VERSION 5.8 ;
BUSBITCHARS "[]" ;
DIVIDERCHAR "/" ;
UNITS
    DATABASE MICRONS 2000 ;
END UNITS

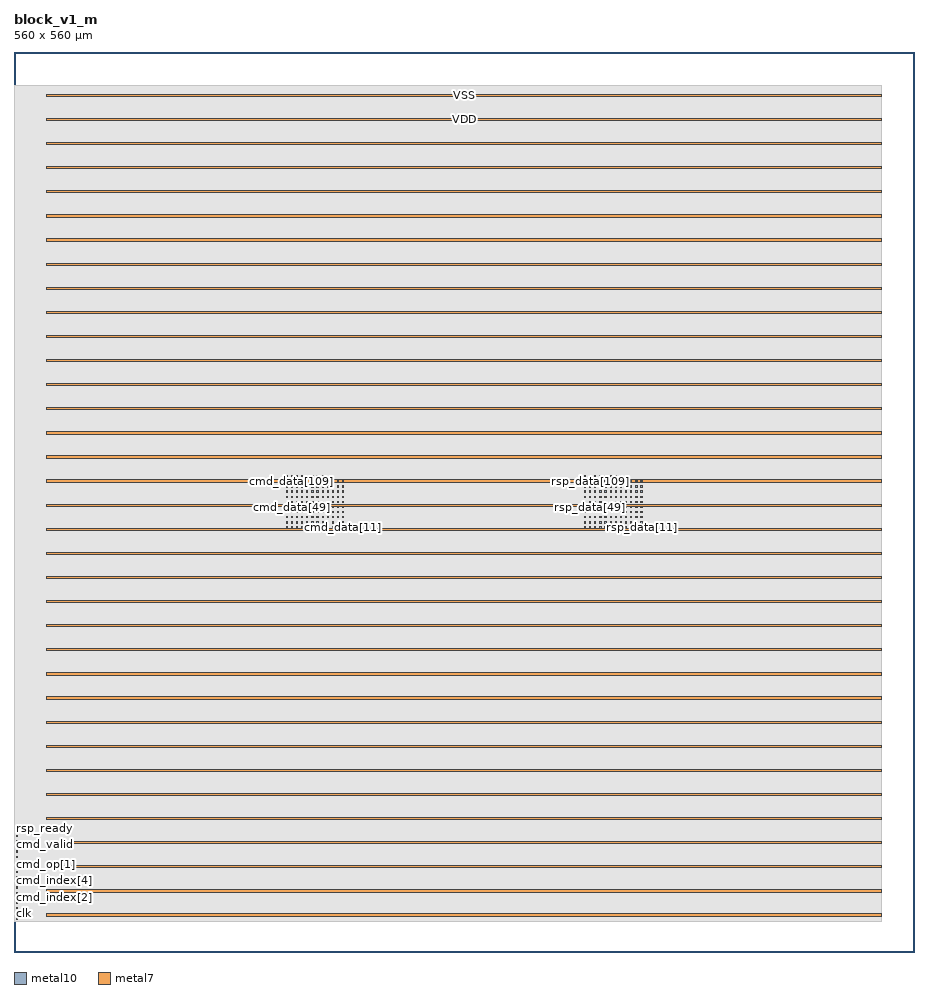
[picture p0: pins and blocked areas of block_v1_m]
MACRO block_v1_m
  FOREIGN block_v1_m 0 0 ;
  CLASS BLOCK ;
  SIZE 560 BY 560 ;
  PIN busy
    DIRECTION OUTPUT ;
    USE SIGNAL ;
    PORT
      LAYER metal10 ;
        RECT  1.295 20.47 2.095 21.27 ;
    END
  END busy
  PIN clk
    DIRECTION INPUT ;
    USE SIGNAL ;
    PORT
      LAYER metal10 ;
        RECT  1.295 23.67 2.095 24.47 ;
    END
  END clk
  PIN cmd_data[0]
    DIRECTION INPUT ;
    USE SIGNAL ;
    PORT
      LAYER metal10 ;
        RECT  169.295 263.67 170.095 264.47 ;
    END
  END cmd_data[0]
  PIN cmd_data[100]
    DIRECTION INPUT ;
    USE SIGNAL ;
    PORT
      LAYER metal10 ;
        RECT  182.095 289.27 182.895 290.07 ;
    END
  END cmd_data[100]
  PIN cmd_data[101]
    DIRECTION INPUT ;
    USE SIGNAL ;
    PORT
      LAYER metal10 ;
        RECT  185.295 289.27 186.095 290.07 ;
    END
  END cmd_data[101]
  PIN cmd_data[102]
    DIRECTION INPUT ;
    USE SIGNAL ;
    PORT
      LAYER metal10 ;
        RECT  188.495 289.27 189.295 290.07 ;
    END
  END cmd_data[102]
  PIN cmd_data[103]
    DIRECTION INPUT ;
    USE SIGNAL ;
    PORT
      LAYER metal10 ;
        RECT  191.695 289.27 192.495 290.07 ;
    END
  END cmd_data[103]
  PIN cmd_data[104]
    DIRECTION INPUT ;
    USE SIGNAL ;
    PORT
      LAYER metal10 ;
        RECT  194.895 289.27 195.695 290.07 ;
    END
  END cmd_data[104]
  PIN cmd_data[105]
    DIRECTION INPUT ;
    USE SIGNAL ;
    PORT
      LAYER metal10 ;
        RECT  198.095 289.27 198.895 290.07 ;
    END
  END cmd_data[105]
  PIN cmd_data[106]
    DIRECTION INPUT ;
    USE SIGNAL ;
    PORT
      LAYER metal10 ;
        RECT  201.295 289.27 202.095 290.07 ;
    END
  END cmd_data[106]
  PIN cmd_data[107]
    DIRECTION INPUT ;
    USE SIGNAL ;
    PORT
      LAYER metal10 ;
        RECT  204.495 289.27 205.295 290.07 ;
    END
  END cmd_data[107]
  PIN cmd_data[108]
    DIRECTION INPUT ;
    USE SIGNAL ;
    PORT
      LAYER metal10 ;
        RECT  169.295 292.47 170.095 293.27 ;
    END
  END cmd_data[108]
  PIN cmd_data[109]
    DIRECTION INPUT ;
    USE SIGNAL ;
    PORT
      LAYER metal10 ;
        RECT  172.495 292.47 173.295 293.27 ;
    END
  END cmd_data[109]
  PIN cmd_data[10]
    DIRECTION INPUT ;
    USE SIGNAL ;
    PORT
      LAYER metal10 ;
        RECT  201.295 263.67 202.095 264.47 ;
    END
  END cmd_data[10]
  PIN cmd_data[110]
    DIRECTION INPUT ;
    USE SIGNAL ;
    PORT
      LAYER metal10 ;
        RECT  175.695 292.47 176.495 293.27 ;
    END
  END cmd_data[110]
  PIN cmd_data[111]
    DIRECTION INPUT ;
    USE SIGNAL ;
    PORT
      LAYER metal10 ;
        RECT  178.895 292.47 179.695 293.27 ;
    END
  END cmd_data[111]
  PIN cmd_data[112]
    DIRECTION INPUT ;
    USE SIGNAL ;
    PORT
      LAYER metal10 ;
        RECT  182.095 292.47 182.895 293.27 ;
    END
  END cmd_data[112]
  PIN cmd_data[113]
    DIRECTION INPUT ;
    USE SIGNAL ;
    PORT
      LAYER metal10 ;
        RECT  185.295 292.47 186.095 293.27 ;
    END
  END cmd_data[113]
  PIN cmd_data[114]
    DIRECTION INPUT ;
    USE SIGNAL ;
    PORT
      LAYER metal10 ;
        RECT  188.495 292.47 189.295 293.27 ;
    END
  END cmd_data[114]
  PIN cmd_data[115]
    DIRECTION INPUT ;
    USE SIGNAL ;
    PORT
      LAYER metal10 ;
        RECT  191.695 292.47 192.495 293.27 ;
    END
  END cmd_data[115]
  PIN cmd_data[116]
    DIRECTION INPUT ;
    USE SIGNAL ;
    PORT
      LAYER metal10 ;
        RECT  194.895 292.47 195.695 293.27 ;
    END
  END cmd_data[116]
  PIN cmd_data[117]
    DIRECTION INPUT ;
    USE SIGNAL ;
    PORT
      LAYER metal10 ;
        RECT  198.095 292.47 198.895 293.27 ;
    END
  END cmd_data[117]
  PIN cmd_data[118]
    DIRECTION INPUT ;
    USE SIGNAL ;
    PORT
      LAYER metal10 ;
        RECT  201.295 292.47 202.095 293.27 ;
    END
  END cmd_data[118]
  PIN cmd_data[119]
    DIRECTION INPUT ;
    USE SIGNAL ;
    PORT
      LAYER metal10 ;
        RECT  204.495 292.47 205.295 293.27 ;
    END
  END cmd_data[119]
  PIN cmd_data[11]
    DIRECTION INPUT ;
    USE SIGNAL ;
    PORT
      LAYER metal10 ;
        RECT  204.495 263.67 205.295 264.47 ;
    END
  END cmd_data[11]
  PIN cmd_data[120]
    DIRECTION INPUT ;
    USE SIGNAL ;
    PORT
      LAYER metal10 ;
        RECT  169.295 295.67 170.095 296.47 ;
    END
  END cmd_data[120]
  PIN cmd_data[121]
    DIRECTION INPUT ;
    USE SIGNAL ;
    PORT
      LAYER metal10 ;
        RECT  172.495 295.67 173.295 296.47 ;
    END
  END cmd_data[121]
  PIN cmd_data[122]
    DIRECTION INPUT ;
    USE SIGNAL ;
    PORT
      LAYER metal10 ;
        RECT  175.695 295.67 176.495 296.47 ;
    END
  END cmd_data[122]
  PIN cmd_data[123]
    DIRECTION INPUT ;
    USE SIGNAL ;
    PORT
      LAYER metal10 ;
        RECT  178.895 295.67 179.695 296.47 ;
    END
  END cmd_data[123]
  PIN cmd_data[124]
    DIRECTION INPUT ;
    USE SIGNAL ;
    PORT
      LAYER metal10 ;
        RECT  182.095 295.67 182.895 296.47 ;
    END
  END cmd_data[124]
  PIN cmd_data[125]
    DIRECTION INPUT ;
    USE SIGNAL ;
    PORT
      LAYER metal10 ;
        RECT  185.295 295.67 186.095 296.47 ;
    END
  END cmd_data[125]
  PIN cmd_data[126]
    DIRECTION INPUT ;
    USE SIGNAL ;
    PORT
      LAYER metal10 ;
        RECT  188.495 295.67 189.295 296.47 ;
    END
  END cmd_data[126]
  PIN cmd_data[127]
    DIRECTION INPUT ;
    USE SIGNAL ;
    PORT
      LAYER metal10 ;
        RECT  191.695 295.67 192.495 296.47 ;
    END
  END cmd_data[127]
  PIN cmd_data[12]
    DIRECTION INPUT ;
    USE SIGNAL ;
    PORT
      LAYER metal10 ;
        RECT  169.295 266.87 170.095 267.67 ;
    END
  END cmd_data[12]
  PIN cmd_data[13]
    DIRECTION INPUT ;
    USE SIGNAL ;
    PORT
      LAYER metal10 ;
        RECT  172.495 266.87 173.295 267.67 ;
    END
  END cmd_data[13]
  PIN cmd_data[14]
    DIRECTION INPUT ;
    USE SIGNAL ;
    PORT
      LAYER metal10 ;
        RECT  175.695 266.87 176.495 267.67 ;
    END
  END cmd_data[14]
  PIN cmd_data[15]
    DIRECTION INPUT ;
    USE SIGNAL ;
    PORT
      LAYER metal10 ;
        RECT  178.895 266.87 179.695 267.67 ;
    END
  END cmd_data[15]
  PIN cmd_data[16]
    DIRECTION INPUT ;
    USE SIGNAL ;
    PORT
      LAYER metal10 ;
        RECT  182.095 266.87 182.895 267.67 ;
    END
  END cmd_data[16]
  PIN cmd_data[17]
    DIRECTION INPUT ;
    USE SIGNAL ;
    PORT
      LAYER metal10 ;
        RECT  185.295 266.87 186.095 267.67 ;
    END
  END cmd_data[17]
  PIN cmd_data[18]
    DIRECTION INPUT ;
    USE SIGNAL ;
    PORT
      LAYER metal10 ;
        RECT  188.495 266.87 189.295 267.67 ;
    END
  END cmd_data[18]
  PIN cmd_data[19]
    DIRECTION INPUT ;
    USE SIGNAL ;
    PORT
      LAYER metal10 ;
        RECT  191.695 266.87 192.495 267.67 ;
    END
  END cmd_data[19]
  PIN cmd_data[1]
    DIRECTION INPUT ;
    USE SIGNAL ;
    PORT
      LAYER metal10 ;
        RECT  172.495 263.67 173.295 264.47 ;
    END
  END cmd_data[1]
  PIN cmd_data[20]
    DIRECTION INPUT ;
    USE SIGNAL ;
    PORT
      LAYER metal10 ;
        RECT  194.895 266.87 195.695 267.67 ;
    END
  END cmd_data[20]
  PIN cmd_data[21]
    DIRECTION INPUT ;
    USE SIGNAL ;
    PORT
      LAYER metal10 ;
        RECT  198.095 266.87 198.895 267.67 ;
    END
  END cmd_data[21]
  PIN cmd_data[22]
    DIRECTION INPUT ;
    USE SIGNAL ;
    PORT
      LAYER metal10 ;
        RECT  201.295 266.87 202.095 267.67 ;
    END
  END cmd_data[22]
  PIN cmd_data[23]
    DIRECTION INPUT ;
    USE SIGNAL ;
    PORT
      LAYER metal10 ;
        RECT  204.495 266.87 205.295 267.67 ;
    END
  END cmd_data[23]
  PIN cmd_data[24]
    DIRECTION INPUT ;
    USE SIGNAL ;
    PORT
      LAYER metal10 ;
        RECT  169.295 270.07 170.095 270.87 ;
    END
  END cmd_data[24]
  PIN cmd_data[25]
    DIRECTION INPUT ;
    USE SIGNAL ;
    PORT
      LAYER metal10 ;
        RECT  172.495 270.07 173.295 270.87 ;
    END
  END cmd_data[25]
  PIN cmd_data[26]
    DIRECTION INPUT ;
    USE SIGNAL ;
    PORT
      LAYER metal10 ;
        RECT  175.695 270.07 176.495 270.87 ;
    END
  END cmd_data[26]
  PIN cmd_data[27]
    DIRECTION INPUT ;
    USE SIGNAL ;
    PORT
      LAYER metal10 ;
        RECT  178.895 270.07 179.695 270.87 ;
    END
  END cmd_data[27]
  PIN cmd_data[28]
    DIRECTION INPUT ;
    USE SIGNAL ;
    PORT
      LAYER metal10 ;
        RECT  182.095 270.07 182.895 270.87 ;
    END
  END cmd_data[28]
  PIN cmd_data[29]
    DIRECTION INPUT ;
    USE SIGNAL ;
    PORT
      LAYER metal10 ;
        RECT  185.295 270.07 186.095 270.87 ;
    END
  END cmd_data[29]
  PIN cmd_data[2]
    DIRECTION INPUT ;
    USE SIGNAL ;
    PORT
      LAYER metal10 ;
        RECT  175.695 263.67 176.495 264.47 ;
    END
  END cmd_data[2]
  PIN cmd_data[30]
    DIRECTION INPUT ;
    USE SIGNAL ;
    PORT
      LAYER metal10 ;
        RECT  188.495 270.07 189.295 270.87 ;
    END
  END cmd_data[30]
  PIN cmd_data[31]
    DIRECTION INPUT ;
    USE SIGNAL ;
    PORT
      LAYER metal10 ;
        RECT  191.695 270.07 192.495 270.87 ;
    END
  END cmd_data[31]
  PIN cmd_data[32]
    DIRECTION INPUT ;
    USE SIGNAL ;
    PORT
      LAYER metal10 ;
        RECT  194.895 270.07 195.695 270.87 ;
    END
  END cmd_data[32]
  PIN cmd_data[33]
    DIRECTION INPUT ;
    USE SIGNAL ;
    PORT
      LAYER metal10 ;
        RECT  198.095 270.07 198.895 270.87 ;
    END
  END cmd_data[33]
  PIN cmd_data[34]
    DIRECTION INPUT ;
    USE SIGNAL ;
    PORT
      LAYER metal10 ;
        RECT  201.295 270.07 202.095 270.87 ;
    END
  END cmd_data[34]
  PIN cmd_data[35]
    DIRECTION INPUT ;
    USE SIGNAL ;
    PORT
      LAYER metal10 ;
        RECT  204.495 270.07 205.295 270.87 ;
    END
  END cmd_data[35]
  PIN cmd_data[36]
    DIRECTION INPUT ;
    USE SIGNAL ;
    PORT
      LAYER metal10 ;
        RECT  169.295 273.27 170.095 274.07 ;
    END
  END cmd_data[36]
  PIN cmd_data[37]
    DIRECTION INPUT ;
    USE SIGNAL ;
    PORT
      LAYER metal10 ;
        RECT  172.495 273.27 173.295 274.07 ;
    END
  END cmd_data[37]
  PIN cmd_data[38]
    DIRECTION INPUT ;
    USE SIGNAL ;
    PORT
      LAYER metal10 ;
        RECT  175.695 273.27 176.495 274.07 ;
    END
  END cmd_data[38]
  PIN cmd_data[39]
    DIRECTION INPUT ;
    USE SIGNAL ;
    PORT
      LAYER metal10 ;
        RECT  178.895 273.27 179.695 274.07 ;
    END
  END cmd_data[39]
  PIN cmd_data[3]
    DIRECTION INPUT ;
    USE SIGNAL ;
    PORT
      LAYER metal10 ;
        RECT  178.895 263.67 179.695 264.47 ;
    END
  END cmd_data[3]
  PIN cmd_data[40]
    DIRECTION INPUT ;
    USE SIGNAL ;
    PORT
      LAYER metal10 ;
        RECT  182.095 273.27 182.895 274.07 ;
    END
  END cmd_data[40]
  PIN cmd_data[41]
    DIRECTION INPUT ;
    USE SIGNAL ;
    PORT
      LAYER metal10 ;
        RECT  185.295 273.27 186.095 274.07 ;
    END
  END cmd_data[41]
  PIN cmd_data[42]
    DIRECTION INPUT ;
    USE SIGNAL ;
    PORT
      LAYER metal10 ;
        RECT  188.495 273.27 189.295 274.07 ;
    END
  END cmd_data[42]
  PIN cmd_data[43]
    DIRECTION INPUT ;
    USE SIGNAL ;
    PORT
      LAYER metal10 ;
        RECT  191.695 273.27 192.495 274.07 ;
    END
  END cmd_data[43]
  PIN cmd_data[44]
    DIRECTION INPUT ;
    USE SIGNAL ;
    PORT
      LAYER metal10 ;
        RECT  194.895 273.27 195.695 274.07 ;
    END
  END cmd_data[44]
  PIN cmd_data[45]
    DIRECTION INPUT ;
    USE SIGNAL ;
    PORT
      LAYER metal10 ;
        RECT  198.095 273.27 198.895 274.07 ;
    END
  END cmd_data[45]
  PIN cmd_data[46]
    DIRECTION INPUT ;
    USE SIGNAL ;
    PORT
      LAYER metal10 ;
        RECT  201.295 273.27 202.095 274.07 ;
    END
  END cmd_data[46]
  PIN cmd_data[47]
    DIRECTION INPUT ;
    USE SIGNAL ;
    PORT
      LAYER metal10 ;
        RECT  204.495 273.27 205.295 274.07 ;
    END
  END cmd_data[47]
  PIN cmd_data[48]
    DIRECTION INPUT ;
    USE SIGNAL ;
    PORT
      LAYER metal10 ;
        RECT  169.295 276.47 170.095 277.27 ;
    END
  END cmd_data[48]
  PIN cmd_data[49]
    DIRECTION INPUT ;
    USE SIGNAL ;
    PORT
      LAYER metal10 ;
        RECT  172.495 276.47 173.295 277.27 ;
    END
  END cmd_data[49]
  PIN cmd_data[4]
    DIRECTION INPUT ;
    USE SIGNAL ;
    PORT
      LAYER metal10 ;
        RECT  182.095 263.67 182.895 264.47 ;
    END
  END cmd_data[4]
  PIN cmd_data[50]
    DIRECTION INPUT ;
    USE SIGNAL ;
    PORT
      LAYER metal10 ;
        RECT  175.695 276.47 176.495 277.27 ;
    END
  END cmd_data[50]
  PIN cmd_data[51]
    DIRECTION INPUT ;
    USE SIGNAL ;
    PORT
      LAYER metal10 ;
        RECT  178.895 276.47 179.695 277.27 ;
    END
  END cmd_data[51]
  PIN cmd_data[52]
    DIRECTION INPUT ;
    USE SIGNAL ;
    PORT
      LAYER metal10 ;
        RECT  182.095 276.47 182.895 277.27 ;
    END
  END cmd_data[52]
  PIN cmd_data[53]
    DIRECTION INPUT ;
    USE SIGNAL ;
    PORT
      LAYER metal10 ;
        RECT  185.295 276.47 186.095 277.27 ;
    END
  END cmd_data[53]
  PIN cmd_data[54]
    DIRECTION INPUT ;
    USE SIGNAL ;
    PORT
      LAYER metal10 ;
        RECT  188.495 276.47 189.295 277.27 ;
    END
  END cmd_data[54]
  PIN cmd_data[55]
    DIRECTION INPUT ;
    USE SIGNAL ;
    PORT
      LAYER metal10 ;
        RECT  191.695 276.47 192.495 277.27 ;
    END
  END cmd_data[55]
  PIN cmd_data[56]
    DIRECTION INPUT ;
    USE SIGNAL ;
    PORT
      LAYER metal10 ;
        RECT  194.895 276.47 195.695 277.27 ;
    END
  END cmd_data[56]
  PIN cmd_data[57]
    DIRECTION INPUT ;
    USE SIGNAL ;
    PORT
      LAYER metal10 ;
        RECT  198.095 276.47 198.895 277.27 ;
    END
  END cmd_data[57]
  PIN cmd_data[58]
    DIRECTION INPUT ;
    USE SIGNAL ;
    PORT
      LAYER metal10 ;
        RECT  201.295 276.47 202.095 277.27 ;
    END
  END cmd_data[58]
  PIN cmd_data[59]
    DIRECTION INPUT ;
    USE SIGNAL ;
    PORT
      LAYER metal10 ;
        RECT  204.495 276.47 205.295 277.27 ;
    END
  END cmd_data[59]
  PIN cmd_data[5]
    DIRECTION INPUT ;
    USE SIGNAL ;
    PORT
      LAYER metal10 ;
        RECT  185.295 263.67 186.095 264.47 ;
    END
  END cmd_data[5]
  PIN cmd_data[60]
    DIRECTION INPUT ;
    USE SIGNAL ;
    PORT
      LAYER metal10 ;
        RECT  169.295 279.67 170.095 280.47 ;
    END
  END cmd_data[60]
  PIN cmd_data[61]
    DIRECTION INPUT ;
    USE SIGNAL ;
    PORT
      LAYER metal10 ;
        RECT  172.495 279.67 173.295 280.47 ;
    END
  END cmd_data[61]
  PIN cmd_data[62]
    DIRECTION INPUT ;
    USE SIGNAL ;
    PORT
      LAYER metal10 ;
        RECT  175.695 279.67 176.495 280.47 ;
    END
  END cmd_data[62]
  PIN cmd_data[63]
    DIRECTION INPUT ;
    USE SIGNAL ;
    PORT
      LAYER metal10 ;
        RECT  178.895 279.67 179.695 280.47 ;
    END
  END cmd_data[63]
  PIN cmd_data[64]
    DIRECTION INPUT ;
    USE SIGNAL ;
    PORT
      LAYER metal10 ;
        RECT  182.095 279.67 182.895 280.47 ;
    END
  END cmd_data[64]
  PIN cmd_data[65]
    DIRECTION INPUT ;
    USE SIGNAL ;
    PORT
      LAYER metal10 ;
        RECT  185.295 279.67 186.095 280.47 ;
    END
  END cmd_data[65]
  PIN cmd_data[66]
    DIRECTION INPUT ;
    USE SIGNAL ;
    PORT
      LAYER metal10 ;
        RECT  188.495 279.67 189.295 280.47 ;
    END
  END cmd_data[66]
  PIN cmd_data[67]
    DIRECTION INPUT ;
    USE SIGNAL ;
    PORT
      LAYER metal10 ;
        RECT  191.695 279.67 192.495 280.47 ;
    END
  END cmd_data[67]
  PIN cmd_data[68]
    DIRECTION INPUT ;
    USE SIGNAL ;
    PORT
      LAYER metal10 ;
        RECT  194.895 279.67 195.695 280.47 ;
    END
  END cmd_data[68]
  PIN cmd_data[69]
    DIRECTION INPUT ;
    USE SIGNAL ;
    PORT
      LAYER metal10 ;
        RECT  198.095 279.67 198.895 280.47 ;
    END
  END cmd_data[69]
  PIN cmd_data[6]
    DIRECTION INPUT ;
    USE SIGNAL ;
    PORT
      LAYER metal10 ;
        RECT  188.495 263.67 189.295 264.47 ;
    END
  END cmd_data[6]
  PIN cmd_data[70]
    DIRECTION INPUT ;
    USE SIGNAL ;
    PORT
      LAYER metal10 ;
        RECT  201.295 279.67 202.095 280.47 ;
    END
  END cmd_data[70]
  PIN cmd_data[71]
    DIRECTION INPUT ;
    USE SIGNAL ;
    PORT
      LAYER metal10 ;
        RECT  204.495 279.67 205.295 280.47 ;
    END
  END cmd_data[71]
  PIN cmd_data[72]
    DIRECTION INPUT ;
    USE SIGNAL ;
    PORT
      LAYER metal10 ;
        RECT  169.295 282.87 170.095 283.67 ;
    END
  END cmd_data[72]
  PIN cmd_data[73]
    DIRECTION INPUT ;
    USE SIGNAL ;
    PORT
      LAYER metal10 ;
        RECT  172.495 282.87 173.295 283.67 ;
    END
  END cmd_data[73]
  PIN cmd_data[74]
    DIRECTION INPUT ;
    USE SIGNAL ;
    PORT
      LAYER metal10 ;
        RECT  175.695 282.87 176.495 283.67 ;
    END
  END cmd_data[74]
  PIN cmd_data[75]
    DIRECTION INPUT ;
    USE SIGNAL ;
    PORT
      LAYER metal10 ;
        RECT  178.895 282.87 179.695 283.67 ;
    END
  END cmd_data[75]
  PIN cmd_data[76]
    DIRECTION INPUT ;
    USE SIGNAL ;
    PORT
      LAYER metal10 ;
        RECT  182.095 282.87 182.895 283.67 ;
    END
  END cmd_data[76]
  PIN cmd_data[77]
    DIRECTION INPUT ;
    USE SIGNAL ;
    PORT
      LAYER metal10 ;
        RECT  185.295 282.87 186.095 283.67 ;
    END
  END cmd_data[77]
  PIN cmd_data[78]
    DIRECTION INPUT ;
    USE SIGNAL ;
    PORT
      LAYER metal10 ;
        RECT  188.495 282.87 189.295 283.67 ;
    END
  END cmd_data[78]
  PIN cmd_data[79]
    DIRECTION INPUT ;
    USE SIGNAL ;
    PORT
      LAYER metal10 ;
        RECT  191.695 282.87 192.495 283.67 ;
    END
  END cmd_data[79]
  PIN cmd_data[7]
    DIRECTION INPUT ;
    USE SIGNAL ;
    PORT
      LAYER metal10 ;
        RECT  191.695 263.67 192.495 264.47 ;
    END
  END cmd_data[7]
  PIN cmd_data[80]
    DIRECTION INPUT ;
    USE SIGNAL ;
    PORT
      LAYER metal10 ;
        RECT  194.895 282.87 195.695 283.67 ;
    END
  END cmd_data[80]
  PIN cmd_data[81]
    DIRECTION INPUT ;
    USE SIGNAL ;
    PORT
      LAYER metal10 ;
        RECT  198.095 282.87 198.895 283.67 ;
    END
  END cmd_data[81]
  PIN cmd_data[82]
    DIRECTION INPUT ;
    USE SIGNAL ;
    PORT
      LAYER metal10 ;
        RECT  201.295 282.87 202.095 283.67 ;
    END
  END cmd_data[82]
  PIN cmd_data[83]
    DIRECTION INPUT ;
    USE SIGNAL ;
    PORT
      LAYER metal10 ;
        RECT  204.495 282.87 205.295 283.67 ;
    END
  END cmd_data[83]
  PIN cmd_data[84]
    DIRECTION INPUT ;
    USE SIGNAL ;
    PORT
      LAYER metal10 ;
        RECT  169.295 286.07 170.095 286.87 ;
    END
  END cmd_data[84]
  PIN cmd_data[85]
    DIRECTION INPUT ;
    USE SIGNAL ;
    PORT
      LAYER metal10 ;
        RECT  172.495 286.07 173.295 286.87 ;
    END
  END cmd_data[85]
  PIN cmd_data[86]
    DIRECTION INPUT ;
    USE SIGNAL ;
    PORT
      LAYER metal10 ;
        RECT  175.695 286.07 176.495 286.87 ;
    END
  END cmd_data[86]
  PIN cmd_data[87]
    DIRECTION INPUT ;
    USE SIGNAL ;
    PORT
      LAYER metal10 ;
        RECT  178.895 286.07 179.695 286.87 ;
    END
  END cmd_data[87]
  PIN cmd_data[88]
    DIRECTION INPUT ;
    USE SIGNAL ;
    PORT
      LAYER metal10 ;
        RECT  182.095 286.07 182.895 286.87 ;
    END
  END cmd_data[88]
  PIN cmd_data[89]
    DIRECTION INPUT ;
    USE SIGNAL ;
    PORT
      LAYER metal10 ;
        RECT  185.295 286.07 186.095 286.87 ;
    END
  END cmd_data[89]
  PIN cmd_data[8]
    DIRECTION INPUT ;
    USE SIGNAL ;
    PORT
      LAYER metal10 ;
        RECT  194.895 263.67 195.695 264.47 ;
    END
  END cmd_data[8]
  PIN cmd_data[90]
    DIRECTION INPUT ;
    USE SIGNAL ;
    PORT
      LAYER metal10 ;
        RECT  188.495 286.07 189.295 286.87 ;
    END
  END cmd_data[90]
  PIN cmd_data[91]
    DIRECTION INPUT ;
    USE SIGNAL ;
    PORT
      LAYER metal10 ;
        RECT  191.695 286.07 192.495 286.87 ;
    END
  END cmd_data[91]
  PIN cmd_data[92]
    DIRECTION INPUT ;
    USE SIGNAL ;
    PORT
      LAYER metal10 ;
        RECT  194.895 286.07 195.695 286.87 ;
    END
  END cmd_data[92]
  PIN cmd_data[93]
    DIRECTION INPUT ;
    USE SIGNAL ;
    PORT
      LAYER metal10 ;
        RECT  198.095 286.07 198.895 286.87 ;
    END
  END cmd_data[93]
  PIN cmd_data[94]
    DIRECTION INPUT ;
    USE SIGNAL ;
    PORT
      LAYER metal10 ;
        RECT  201.295 286.07 202.095 286.87 ;
    END
  END cmd_data[94]
  PIN cmd_data[95]
    DIRECTION INPUT ;
    USE SIGNAL ;
    PORT
      LAYER metal10 ;
        RECT  204.495 286.07 205.295 286.87 ;
    END
  END cmd_data[95]
  PIN cmd_data[96]
    DIRECTION INPUT ;
    USE SIGNAL ;
    PORT
      LAYER metal10 ;
        RECT  169.295 289.27 170.095 290.07 ;
    END
  END cmd_data[96]
  PIN cmd_data[97]
    DIRECTION INPUT ;
    USE SIGNAL ;
    PORT
      LAYER metal10 ;
        RECT  172.495 289.27 173.295 290.07 ;
    END
  END cmd_data[97]
  PIN cmd_data[98]
    DIRECTION INPUT ;
    USE SIGNAL ;
    PORT
      LAYER metal10 ;
        RECT  175.695 289.27 176.495 290.07 ;
    END
  END cmd_data[98]
  PIN cmd_data[99]
    DIRECTION INPUT ;
    USE SIGNAL ;
    PORT
      LAYER metal10 ;
        RECT  178.895 289.27 179.695 290.07 ;
    END
  END cmd_data[99]
  PIN cmd_data[9]
    DIRECTION INPUT ;
    USE SIGNAL ;
    PORT
      LAYER metal10 ;
        RECT  198.095 263.67 198.895 264.47 ;
    END
  END cmd_data[9]
  PIN cmd_index[0]
    DIRECTION INPUT ;
    USE SIGNAL ;
    PORT
      LAYER metal10 ;
        RECT  1.295 26.87 2.095 27.67 ;
    END
  END cmd_index[0]
  PIN cmd_index[1]
    DIRECTION INPUT ;
    USE SIGNAL ;
    PORT
      LAYER metal10 ;
        RECT  1.295 30.07 2.095 30.87 ;
    END
  END cmd_index[1]
  PIN cmd_index[2]
    DIRECTION INPUT ;
    USE SIGNAL ;
    PORT
      LAYER metal10 ;
        RECT  1.295 33.27 2.095 34.07 ;
    END
  END cmd_index[2]
  PIN cmd_index[3]
    DIRECTION INPUT ;
    USE SIGNAL ;
    PORT
      LAYER metal10 ;
        RECT  1.295 36.47 2.095 37.27 ;
    END
  END cmd_index[3]
  PIN cmd_index[4]
    DIRECTION INPUT ;
    USE SIGNAL ;
    PORT
      LAYER metal10 ;
        RECT  1.295 39.67 2.095 40.47 ;
    END
  END cmd_index[4]
  PIN cmd_index[5]
    DIRECTION INPUT ;
    USE SIGNAL ;
    PORT
      LAYER metal10 ;
        RECT  1.295 42.87 2.095 43.67 ;
    END
  END cmd_index[5]
  PIN cmd_op[0]
    DIRECTION INPUT ;
    USE SIGNAL ;
    PORT
      LAYER metal10 ;
        RECT  1.295 46.07 2.095 46.87 ;
    END
  END cmd_op[0]
  PIN cmd_op[1]
    DIRECTION INPUT ;
    USE SIGNAL ;
    PORT
      LAYER metal10 ;
        RECT  1.295 49.27 2.095 50.07 ;
    END
  END cmd_op[1]
  PIN cmd_op[2]
    DIRECTION INPUT ;
    USE SIGNAL ;
    PORT
      LAYER metal10 ;
        RECT  1.295 52.47 2.095 53.27 ;
    END
  END cmd_op[2]
  PIN cmd_op[3]
    DIRECTION INPUT ;
    USE SIGNAL ;
    PORT
      LAYER metal10 ;
        RECT  1.295 55.67 2.095 56.47 ;
    END
  END cmd_op[3]
  PIN cmd_ready
    DIRECTION OUTPUT ;
    USE SIGNAL ;
    PORT
      LAYER metal10 ;
        RECT  1.295 58.87 2.095 59.67 ;
    END
  END cmd_ready
  PIN cmd_valid
    DIRECTION INPUT ;
    USE SIGNAL ;
    PORT
      LAYER metal10 ;
        RECT  1.295 62.07 2.095 62.87 ;
    END
  END cmd_valid
  PIN reset
    DIRECTION INPUT ;
    USE SIGNAL ;
    PORT
      LAYER metal10 ;
        RECT  1.295 65.27 2.095 66.07 ;
    END
  END reset
  PIN rsp_data[0]
    DIRECTION OUTPUT ;
    USE SIGNAL ;
    PORT
      LAYER metal10 ;
        RECT  354.895 263.67 355.695 264.47 ;
    END
  END rsp_data[0]
  PIN rsp_data[100]
    DIRECTION OUTPUT ;
    USE SIGNAL ;
    PORT
      LAYER metal10 ;
        RECT  367.695 289.27 368.495 290.07 ;
    END
  END rsp_data[100]
  PIN rsp_data[101]
    DIRECTION OUTPUT ;
    USE SIGNAL ;
    PORT
      LAYER metal10 ;
        RECT  370.895 289.27 371.695 290.07 ;
    END
  END rsp_data[101]
  PIN rsp_data[102]
    DIRECTION OUTPUT ;
    USE SIGNAL ;
    PORT
      LAYER metal10 ;
        RECT  374.095 289.27 374.895 290.07 ;
    END
  END rsp_data[102]
  PIN rsp_data[103]
    DIRECTION OUTPUT ;
    USE SIGNAL ;
    PORT
      LAYER metal10 ;
        RECT  377.295 289.27 378.095 290.07 ;
    END
  END rsp_data[103]
  PIN rsp_data[104]
    DIRECTION OUTPUT ;
    USE SIGNAL ;
    PORT
      LAYER metal10 ;
        RECT  380.495 289.27 381.295 290.07 ;
    END
  END rsp_data[104]
  PIN rsp_data[105]
    DIRECTION OUTPUT ;
    USE SIGNAL ;
    PORT
      LAYER metal10 ;
        RECT  383.695 289.27 384.495 290.07 ;
    END
  END rsp_data[105]
  PIN rsp_data[106]
    DIRECTION OUTPUT ;
    USE SIGNAL ;
    PORT
      LAYER metal10 ;
        RECT  386.895 289.27 387.695 290.07 ;
    END
  END rsp_data[106]
  PIN rsp_data[107]
    DIRECTION OUTPUT ;
    USE SIGNAL ;
    PORT
      LAYER metal10 ;
        RECT  390.095 289.27 390.895 290.07 ;
    END
  END rsp_data[107]
  PIN rsp_data[108]
    DIRECTION OUTPUT ;
    USE SIGNAL ;
    PORT
      LAYER metal10 ;
        RECT  354.895 292.47 355.695 293.27 ;
    END
  END rsp_data[108]
  PIN rsp_data[109]
    DIRECTION OUTPUT ;
    USE SIGNAL ;
    PORT
      LAYER metal10 ;
        RECT  358.095 292.47 358.895 293.27 ;
    END
  END rsp_data[109]
  PIN rsp_data[10]
    DIRECTION OUTPUT ;
    USE SIGNAL ;
    PORT
      LAYER metal10 ;
        RECT  386.895 263.67 387.695 264.47 ;
    END
  END rsp_data[10]
  PIN rsp_data[110]
    DIRECTION OUTPUT ;
    USE SIGNAL ;
    PORT
      LAYER metal10 ;
        RECT  361.295 292.47 362.095 293.27 ;
    END
  END rsp_data[110]
  PIN rsp_data[111]
    DIRECTION OUTPUT ;
    USE SIGNAL ;
    PORT
      LAYER metal10 ;
        RECT  364.495 292.47 365.295 293.27 ;
    END
  END rsp_data[111]
  PIN rsp_data[112]
    DIRECTION OUTPUT ;
    USE SIGNAL ;
    PORT
      LAYER metal10 ;
        RECT  367.695 292.47 368.495 293.27 ;
    END
  END rsp_data[112]
  PIN rsp_data[113]
    DIRECTION OUTPUT ;
    USE SIGNAL ;
    PORT
      LAYER metal10 ;
        RECT  370.895 292.47 371.695 293.27 ;
    END
  END rsp_data[113]
  PIN rsp_data[114]
    DIRECTION OUTPUT ;
    USE SIGNAL ;
    PORT
      LAYER metal10 ;
        RECT  374.095 292.47 374.895 293.27 ;
    END
  END rsp_data[114]
  PIN rsp_data[115]
    DIRECTION OUTPUT ;
    USE SIGNAL ;
    PORT
      LAYER metal10 ;
        RECT  377.295 292.47 378.095 293.27 ;
    END
  END rsp_data[115]
  PIN rsp_data[116]
    DIRECTION OUTPUT ;
    USE SIGNAL ;
    PORT
      LAYER metal10 ;
        RECT  380.495 292.47 381.295 293.27 ;
    END
  END rsp_data[116]
  PIN rsp_data[117]
    DIRECTION OUTPUT ;
    USE SIGNAL ;
    PORT
      LAYER metal10 ;
        RECT  383.695 292.47 384.495 293.27 ;
    END
  END rsp_data[117]
  PIN rsp_data[118]
    DIRECTION OUTPUT ;
    USE SIGNAL ;
    PORT
      LAYER metal10 ;
        RECT  386.895 292.47 387.695 293.27 ;
    END
  END rsp_data[118]
  PIN rsp_data[119]
    DIRECTION OUTPUT ;
    USE SIGNAL ;
    PORT
      LAYER metal10 ;
        RECT  390.095 292.47 390.895 293.27 ;
    END
  END rsp_data[119]
  PIN rsp_data[11]
    DIRECTION OUTPUT ;
    USE SIGNAL ;
    PORT
      LAYER metal10 ;
        RECT  390.095 263.67 390.895 264.47 ;
    END
  END rsp_data[11]
  PIN rsp_data[120]
    DIRECTION OUTPUT ;
    USE SIGNAL ;
    PORT
      LAYER metal10 ;
        RECT  354.895 295.67 355.695 296.47 ;
    END
  END rsp_data[120]
  PIN rsp_data[121]
    DIRECTION OUTPUT ;
    USE SIGNAL ;
    PORT
      LAYER metal10 ;
        RECT  358.095 295.67 358.895 296.47 ;
    END
  END rsp_data[121]
  PIN rsp_data[122]
    DIRECTION OUTPUT ;
    USE SIGNAL ;
    PORT
      LAYER metal10 ;
        RECT  361.295 295.67 362.095 296.47 ;
    END
  END rsp_data[122]
  PIN rsp_data[123]
    DIRECTION OUTPUT ;
    USE SIGNAL ;
    PORT
      LAYER metal10 ;
        RECT  364.495 295.67 365.295 296.47 ;
    END
  END rsp_data[123]
  PIN rsp_data[124]
    DIRECTION OUTPUT ;
    USE SIGNAL ;
    PORT
      LAYER metal10 ;
        RECT  367.695 295.67 368.495 296.47 ;
    END
  END rsp_data[124]
  PIN rsp_data[125]
    DIRECTION OUTPUT ;
    USE SIGNAL ;
    PORT
      LAYER metal10 ;
        RECT  370.895 295.67 371.695 296.47 ;
    END
  END rsp_data[125]
  PIN rsp_data[126]
    DIRECTION OUTPUT ;
    USE SIGNAL ;
    PORT
      LAYER metal10 ;
        RECT  374.095 295.67 374.895 296.47 ;
    END
  END rsp_data[126]
  PIN rsp_data[127]
    DIRECTION OUTPUT ;
    USE SIGNAL ;
    PORT
      LAYER metal10 ;
        RECT  377.295 295.67 378.095 296.47 ;
    END
  END rsp_data[127]
  PIN rsp_data[12]
    DIRECTION OUTPUT ;
    USE SIGNAL ;
    PORT
      LAYER metal10 ;
        RECT  354.895 266.87 355.695 267.67 ;
    END
  END rsp_data[12]
  PIN rsp_data[13]
    DIRECTION OUTPUT ;
    USE SIGNAL ;
    PORT
      LAYER metal10 ;
        RECT  358.095 266.87 358.895 267.67 ;
    END
  END rsp_data[13]
  PIN rsp_data[14]
    DIRECTION OUTPUT ;
    USE SIGNAL ;
    PORT
      LAYER metal10 ;
        RECT  361.295 266.87 362.095 267.67 ;
    END
  END rsp_data[14]
  PIN rsp_data[15]
    DIRECTION OUTPUT ;
    USE SIGNAL ;
    PORT
      LAYER metal10 ;
        RECT  364.495 266.87 365.295 267.67 ;
    END
  END rsp_data[15]
  PIN rsp_data[16]
    DIRECTION OUTPUT ;
    USE SIGNAL ;
    PORT
      LAYER metal10 ;
        RECT  367.695 266.87 368.495 267.67 ;
    END
  END rsp_data[16]
  PIN rsp_data[17]
    DIRECTION OUTPUT ;
    USE SIGNAL ;
    PORT
      LAYER metal10 ;
        RECT  370.895 266.87 371.695 267.67 ;
    END
  END rsp_data[17]
  PIN rsp_data[18]
    DIRECTION OUTPUT ;
    USE SIGNAL ;
    PORT
      LAYER metal10 ;
        RECT  374.095 266.87 374.895 267.67 ;
    END
  END rsp_data[18]
  PIN rsp_data[19]
    DIRECTION OUTPUT ;
    USE SIGNAL ;
    PORT
      LAYER metal10 ;
        RECT  377.295 266.87 378.095 267.67 ;
    END
  END rsp_data[19]
  PIN rsp_data[1]
    DIRECTION OUTPUT ;
    USE SIGNAL ;
    PORT
      LAYER metal10 ;
        RECT  358.095 263.67 358.895 264.47 ;
    END
  END rsp_data[1]
  PIN rsp_data[20]
    DIRECTION OUTPUT ;
    USE SIGNAL ;
    PORT
      LAYER metal10 ;
        RECT  380.495 266.87 381.295 267.67 ;
    END
  END rsp_data[20]
  PIN rsp_data[21]
    DIRECTION OUTPUT ;
    USE SIGNAL ;
    PORT
      LAYER metal10 ;
        RECT  383.695 266.87 384.495 267.67 ;
    END
  END rsp_data[21]
  PIN rsp_data[22]
    DIRECTION OUTPUT ;
    USE SIGNAL ;
    PORT
      LAYER metal10 ;
        RECT  386.895 266.87 387.695 267.67 ;
    END
  END rsp_data[22]
  PIN rsp_data[23]
    DIRECTION OUTPUT ;
    USE SIGNAL ;
    PORT
      LAYER metal10 ;
        RECT  390.095 266.87 390.895 267.67 ;
    END
  END rsp_data[23]
  PIN rsp_data[24]
    DIRECTION OUTPUT ;
    USE SIGNAL ;
    PORT
      LAYER metal10 ;
        RECT  354.895 270.07 355.695 270.87 ;
    END
  END rsp_data[24]
  PIN rsp_data[25]
    DIRECTION OUTPUT ;
    USE SIGNAL ;
    PORT
      LAYER metal10 ;
        RECT  358.095 270.07 358.895 270.87 ;
    END
  END rsp_data[25]
  PIN rsp_data[26]
    DIRECTION OUTPUT ;
    USE SIGNAL ;
    PORT
      LAYER metal10 ;
        RECT  361.295 270.07 362.095 270.87 ;
    END
  END rsp_data[26]
  PIN rsp_data[27]
    DIRECTION OUTPUT ;
    USE SIGNAL ;
    PORT
      LAYER metal10 ;
        RECT  364.495 270.07 365.295 270.87 ;
    END
  END rsp_data[27]
  PIN rsp_data[28]
    DIRECTION OUTPUT ;
    USE SIGNAL ;
    PORT
      LAYER metal10 ;
        RECT  367.695 270.07 368.495 270.87 ;
    END
  END rsp_data[28]
  PIN rsp_data[29]
    DIRECTION OUTPUT ;
    USE SIGNAL ;
    PORT
      LAYER metal10 ;
        RECT  370.895 270.07 371.695 270.87 ;
    END
  END rsp_data[29]
  PIN rsp_data[2]
    DIRECTION OUTPUT ;
    USE SIGNAL ;
    PORT
      LAYER metal10 ;
        RECT  361.295 263.67 362.095 264.47 ;
    END
  END rsp_data[2]
  PIN rsp_data[30]
    DIRECTION OUTPUT ;
    USE SIGNAL ;
    PORT
      LAYER metal10 ;
        RECT  374.095 270.07 374.895 270.87 ;
    END
  END rsp_data[30]
  PIN rsp_data[31]
    DIRECTION OUTPUT ;
    USE SIGNAL ;
    PORT
      LAYER metal10 ;
        RECT  377.295 270.07 378.095 270.87 ;
    END
  END rsp_data[31]
  PIN rsp_data[32]
    DIRECTION OUTPUT ;
    USE SIGNAL ;
    PORT
      LAYER metal10 ;
        RECT  380.495 270.07 381.295 270.87 ;
    END
  END rsp_data[32]
  PIN rsp_data[33]
    DIRECTION OUTPUT ;
    USE SIGNAL ;
    PORT
      LAYER metal10 ;
        RECT  383.695 270.07 384.495 270.87 ;
    END
  END rsp_data[33]
  PIN rsp_data[34]
    DIRECTION OUTPUT ;
    USE SIGNAL ;
    PORT
      LAYER metal10 ;
        RECT  386.895 270.07 387.695 270.87 ;
    END
  END rsp_data[34]
  PIN rsp_data[35]
    DIRECTION OUTPUT ;
    USE SIGNAL ;
    PORT
      LAYER metal10 ;
        RECT  390.095 270.07 390.895 270.87 ;
    END
  END rsp_data[35]
  PIN rsp_data[36]
    DIRECTION OUTPUT ;
    USE SIGNAL ;
    PORT
      LAYER metal10 ;
        RECT  354.895 273.27 355.695 274.07 ;
    END
  END rsp_data[36]
  PIN rsp_data[37]
    DIRECTION OUTPUT ;
    USE SIGNAL ;
    PORT
      LAYER metal10 ;
        RECT  358.095 273.27 358.895 274.07 ;
    END
  END rsp_data[37]
  PIN rsp_data[38]
    DIRECTION OUTPUT ;
    USE SIGNAL ;
    PORT
      LAYER metal10 ;
        RECT  361.295 273.27 362.095 274.07 ;
    END
  END rsp_data[38]
  PIN rsp_data[39]
    DIRECTION OUTPUT ;
    USE SIGNAL ;
    PORT
      LAYER metal10 ;
        RECT  364.495 273.27 365.295 274.07 ;
    END
  END rsp_data[39]
  PIN rsp_data[3]
    DIRECTION OUTPUT ;
    USE SIGNAL ;
    PORT
      LAYER metal10 ;
        RECT  364.495 263.67 365.295 264.47 ;
    END
  END rsp_data[3]
  PIN rsp_data[40]
    DIRECTION OUTPUT ;
    USE SIGNAL ;
    PORT
      LAYER metal10 ;
        RECT  367.695 273.27 368.495 274.07 ;
    END
  END rsp_data[40]
  PIN rsp_data[41]
    DIRECTION OUTPUT ;
    USE SIGNAL ;
    PORT
      LAYER metal10 ;
        RECT  370.895 273.27 371.695 274.07 ;
    END
  END rsp_data[41]
  PIN rsp_data[42]
    DIRECTION OUTPUT ;
    USE SIGNAL ;
    PORT
      LAYER metal10 ;
        RECT  374.095 273.27 374.895 274.07 ;
    END
  END rsp_data[42]
  PIN rsp_data[43]
    DIRECTION OUTPUT ;
    USE SIGNAL ;
    PORT
      LAYER metal10 ;
        RECT  377.295 273.27 378.095 274.07 ;
    END
  END rsp_data[43]
  PIN rsp_data[44]
    DIRECTION OUTPUT ;
    USE SIGNAL ;
    PORT
      LAYER metal10 ;
        RECT  380.495 273.27 381.295 274.07 ;
    END
  END rsp_data[44]
  PIN rsp_data[45]
    DIRECTION OUTPUT ;
    USE SIGNAL ;
    PORT
      LAYER metal10 ;
        RECT  383.695 273.27 384.495 274.07 ;
    END
  END rsp_data[45]
  PIN rsp_data[46]
    DIRECTION OUTPUT ;
    USE SIGNAL ;
    PORT
      LAYER metal10 ;
        RECT  386.895 273.27 387.695 274.07 ;
    END
  END rsp_data[46]
  PIN rsp_data[47]
    DIRECTION OUTPUT ;
    USE SIGNAL ;
    PORT
      LAYER metal10 ;
        RECT  390.095 273.27 390.895 274.07 ;
    END
  END rsp_data[47]
  PIN rsp_data[48]
    DIRECTION OUTPUT ;
    USE SIGNAL ;
    PORT
      LAYER metal10 ;
        RECT  354.895 276.47 355.695 277.27 ;
    END
  END rsp_data[48]
  PIN rsp_data[49]
    DIRECTION OUTPUT ;
    USE SIGNAL ;
    PORT
      LAYER metal10 ;
        RECT  358.095 276.47 358.895 277.27 ;
    END
  END rsp_data[49]
  PIN rsp_data[4]
    DIRECTION OUTPUT ;
    USE SIGNAL ;
    PORT
      LAYER metal10 ;
        RECT  367.695 263.67 368.495 264.47 ;
    END
  END rsp_data[4]
  PIN rsp_data[50]
    DIRECTION OUTPUT ;
    USE SIGNAL ;
    PORT
      LAYER metal10 ;
        RECT  361.295 276.47 362.095 277.27 ;
    END
  END rsp_data[50]
  PIN rsp_data[51]
    DIRECTION OUTPUT ;
    USE SIGNAL ;
    PORT
      LAYER metal10 ;
        RECT  364.495 276.47 365.295 277.27 ;
    END
  END rsp_data[51]
  PIN rsp_data[52]
    DIRECTION OUTPUT ;
    USE SIGNAL ;
    PORT
      LAYER metal10 ;
        RECT  367.695 276.47 368.495 277.27 ;
    END
  END rsp_data[52]
  PIN rsp_data[53]
    DIRECTION OUTPUT ;
    USE SIGNAL ;
    PORT
      LAYER metal10 ;
        RECT  370.895 276.47 371.695 277.27 ;
    END
  END rsp_data[53]
  PIN rsp_data[54]
    DIRECTION OUTPUT ;
    USE SIGNAL ;
    PORT
      LAYER metal10 ;
        RECT  374.095 276.47 374.895 277.27 ;
    END
  END rsp_data[54]
  PIN rsp_data[55]
    DIRECTION OUTPUT ;
    USE SIGNAL ;
    PORT
      LAYER metal10 ;
        RECT  377.295 276.47 378.095 277.27 ;
    END
  END rsp_data[55]
  PIN rsp_data[56]
    DIRECTION OUTPUT ;
    USE SIGNAL ;
    PORT
      LAYER metal10 ;
        RECT  380.495 276.47 381.295 277.27 ;
    END
  END rsp_data[56]
  PIN rsp_data[57]
    DIRECTION OUTPUT ;
    USE SIGNAL ;
    PORT
      LAYER metal10 ;
        RECT  383.695 276.47 384.495 277.27 ;
    END
  END rsp_data[57]
  PIN rsp_data[58]
    DIRECTION OUTPUT ;
    USE SIGNAL ;
    PORT
      LAYER metal10 ;
        RECT  386.895 276.47 387.695 277.27 ;
    END
  END rsp_data[58]
  PIN rsp_data[59]
    DIRECTION OUTPUT ;
    USE SIGNAL ;
    PORT
      LAYER metal10 ;
        RECT  390.095 276.47 390.895 277.27 ;
    END
  END rsp_data[59]
  PIN rsp_data[5]
    DIRECTION OUTPUT ;
    USE SIGNAL ;
    PORT
      LAYER metal10 ;
        RECT  370.895 263.67 371.695 264.47 ;
    END
  END rsp_data[5]
  PIN rsp_data[60]
    DIRECTION OUTPUT ;
    USE SIGNAL ;
    PORT
      LAYER metal10 ;
        RECT  354.895 279.67 355.695 280.47 ;
    END
  END rsp_data[60]
  PIN rsp_data[61]
    DIRECTION OUTPUT ;
    USE SIGNAL ;
    PORT
      LAYER metal10 ;
        RECT  358.095 279.67 358.895 280.47 ;
    END
  END rsp_data[61]
  PIN rsp_data[62]
    DIRECTION OUTPUT ;
    USE SIGNAL ;
    PORT
      LAYER metal10 ;
        RECT  361.295 279.67 362.095 280.47 ;
    END
  END rsp_data[62]
  PIN rsp_data[63]
    DIRECTION OUTPUT ;
    USE SIGNAL ;
    PORT
      LAYER metal10 ;
        RECT  364.495 279.67 365.295 280.47 ;
    END
  END rsp_data[63]
  PIN rsp_data[64]
    DIRECTION OUTPUT ;
    USE SIGNAL ;
    PORT
      LAYER metal10 ;
        RECT  367.695 279.67 368.495 280.47 ;
    END
  END rsp_data[64]
  PIN rsp_data[65]
    DIRECTION OUTPUT ;
    USE SIGNAL ;
    PORT
      LAYER metal10 ;
        RECT  370.895 279.67 371.695 280.47 ;
    END
  END rsp_data[65]
  PIN rsp_data[66]
    DIRECTION OUTPUT ;
    USE SIGNAL ;
    PORT
      LAYER metal10 ;
        RECT  374.095 279.67 374.895 280.47 ;
    END
  END rsp_data[66]
  PIN rsp_data[67]
    DIRECTION OUTPUT ;
    USE SIGNAL ;
    PORT
      LAYER metal10 ;
        RECT  377.295 279.67 378.095 280.47 ;
    END
  END rsp_data[67]
  PIN rsp_data[68]
    DIRECTION OUTPUT ;
    USE SIGNAL ;
    PORT
      LAYER metal10 ;
        RECT  380.495 279.67 381.295 280.47 ;
    END
  END rsp_data[68]
  PIN rsp_data[69]
    DIRECTION OUTPUT ;
    USE SIGNAL ;
    PORT
      LAYER metal10 ;
        RECT  383.695 279.67 384.495 280.47 ;
    END
  END rsp_data[69]
  PIN rsp_data[6]
    DIRECTION OUTPUT ;
    USE SIGNAL ;
    PORT
      LAYER metal10 ;
        RECT  374.095 263.67 374.895 264.47 ;
    END
  END rsp_data[6]
  PIN rsp_data[70]
    DIRECTION OUTPUT ;
    USE SIGNAL ;
    PORT
      LAYER metal10 ;
        RECT  386.895 279.67 387.695 280.47 ;
    END
  END rsp_data[70]
  PIN rsp_data[71]
    DIRECTION OUTPUT ;
    USE SIGNAL ;
    PORT
      LAYER metal10 ;
        RECT  390.095 279.67 390.895 280.47 ;
    END
  END rsp_data[71]
  PIN rsp_data[72]
    DIRECTION OUTPUT ;
    USE SIGNAL ;
    PORT
      LAYER metal10 ;
        RECT  354.895 282.87 355.695 283.67 ;
    END
  END rsp_data[72]
  PIN rsp_data[73]
    DIRECTION OUTPUT ;
    USE SIGNAL ;
    PORT
      LAYER metal10 ;
        RECT  358.095 282.87 358.895 283.67 ;
    END
  END rsp_data[73]
  PIN rsp_data[74]
    DIRECTION OUTPUT ;
    USE SIGNAL ;
    PORT
      LAYER metal10 ;
        RECT  361.295 282.87 362.095 283.67 ;
    END
  END rsp_data[74]
  PIN rsp_data[75]
    DIRECTION OUTPUT ;
    USE SIGNAL ;
    PORT
      LAYER metal10 ;
        RECT  364.495 282.87 365.295 283.67 ;
    END
  END rsp_data[75]
  PIN rsp_data[76]
    DIRECTION OUTPUT ;
    USE SIGNAL ;
    PORT
      LAYER metal10 ;
        RECT  367.695 282.87 368.495 283.67 ;
    END
  END rsp_data[76]
  PIN rsp_data[77]
    DIRECTION OUTPUT ;
    USE SIGNAL ;
    PORT
      LAYER metal10 ;
        RECT  370.895 282.87 371.695 283.67 ;
    END
  END rsp_data[77]
  PIN rsp_data[78]
    DIRECTION OUTPUT ;
    USE SIGNAL ;
    PORT
      LAYER metal10 ;
        RECT  374.095 282.87 374.895 283.67 ;
    END
  END rsp_data[78]
  PIN rsp_data[79]
    DIRECTION OUTPUT ;
    USE SIGNAL ;
    PORT
      LAYER metal10 ;
        RECT  377.295 282.87 378.095 283.67 ;
    END
  END rsp_data[79]
  PIN rsp_data[7]
    DIRECTION OUTPUT ;
    USE SIGNAL ;
    PORT
      LAYER metal10 ;
        RECT  377.295 263.67 378.095 264.47 ;
    END
  END rsp_data[7]
  PIN rsp_data[80]
    DIRECTION OUTPUT ;
    USE SIGNAL ;
    PORT
      LAYER metal10 ;
        RECT  380.495 282.87 381.295 283.67 ;
    END
  END rsp_data[80]
  PIN rsp_data[81]
    DIRECTION OUTPUT ;
    USE SIGNAL ;
    PORT
      LAYER metal10 ;
        RECT  383.695 282.87 384.495 283.67 ;
    END
  END rsp_data[81]
  PIN rsp_data[82]
    DIRECTION OUTPUT ;
    USE SIGNAL ;
    PORT
      LAYER metal10 ;
        RECT  386.895 282.87 387.695 283.67 ;
    END
  END rsp_data[82]
  PIN rsp_data[83]
    DIRECTION OUTPUT ;
    USE SIGNAL ;
    PORT
      LAYER metal10 ;
        RECT  390.095 282.87 390.895 283.67 ;
    END
  END rsp_data[83]
  PIN rsp_data[84]
    DIRECTION OUTPUT ;
    USE SIGNAL ;
    PORT
      LAYER metal10 ;
        RECT  354.895 286.07 355.695 286.87 ;
    END
  END rsp_data[84]
  PIN rsp_data[85]
    DIRECTION OUTPUT ;
    USE SIGNAL ;
    PORT
      LAYER metal10 ;
        RECT  358.095 286.07 358.895 286.87 ;
    END
  END rsp_data[85]
  PIN rsp_data[86]
    DIRECTION OUTPUT ;
    USE SIGNAL ;
    PORT
      LAYER metal10 ;
        RECT  361.295 286.07 362.095 286.87 ;
    END
  END rsp_data[86]
  PIN rsp_data[87]
    DIRECTION OUTPUT ;
    USE SIGNAL ;
    PORT
      LAYER metal10 ;
        RECT  364.495 286.07 365.295 286.87 ;
    END
  END rsp_data[87]
  PIN rsp_data[88]
    DIRECTION OUTPUT ;
    USE SIGNAL ;
    PORT
      LAYER metal10 ;
        RECT  367.695 286.07 368.495 286.87 ;
    END
  END rsp_data[88]
  PIN rsp_data[89]
    DIRECTION OUTPUT ;
    USE SIGNAL ;
    PORT
      LAYER metal10 ;
        RECT  370.895 286.07 371.695 286.87 ;
    END
  END rsp_data[89]
  PIN rsp_data[8]
    DIRECTION OUTPUT ;
    USE SIGNAL ;
    PORT
      LAYER metal10 ;
        RECT  380.495 263.67 381.295 264.47 ;
    END
  END rsp_data[8]
  PIN rsp_data[90]
    DIRECTION OUTPUT ;
    USE SIGNAL ;
    PORT
      LAYER metal10 ;
        RECT  374.095 286.07 374.895 286.87 ;
    END
  END rsp_data[90]
  PIN rsp_data[91]
    DIRECTION OUTPUT ;
    USE SIGNAL ;
    PORT
      LAYER metal10 ;
        RECT  377.295 286.07 378.095 286.87 ;
    END
  END rsp_data[91]
  PIN rsp_data[92]
    DIRECTION OUTPUT ;
    USE SIGNAL ;
    PORT
      LAYER metal10 ;
        RECT  380.495 286.07 381.295 286.87 ;
    END
  END rsp_data[92]
  PIN rsp_data[93]
    DIRECTION OUTPUT ;
    USE SIGNAL ;
    PORT
      LAYER metal10 ;
        RECT  383.695 286.07 384.495 286.87 ;
    END
  END rsp_data[93]
  PIN rsp_data[94]
    DIRECTION OUTPUT ;
    USE SIGNAL ;
    PORT
      LAYER metal10 ;
        RECT  386.895 286.07 387.695 286.87 ;
    END
  END rsp_data[94]
  PIN rsp_data[95]
    DIRECTION OUTPUT ;
    USE SIGNAL ;
    PORT
      LAYER metal10 ;
        RECT  390.095 286.07 390.895 286.87 ;
    END
  END rsp_data[95]
  PIN rsp_data[96]
    DIRECTION OUTPUT ;
    USE SIGNAL ;
    PORT
      LAYER metal10 ;
        RECT  354.895 289.27 355.695 290.07 ;
    END
  END rsp_data[96]
  PIN rsp_data[97]
    DIRECTION OUTPUT ;
    USE SIGNAL ;
    PORT
      LAYER metal10 ;
        RECT  358.095 289.27 358.895 290.07 ;
    END
  END rsp_data[97]
  PIN rsp_data[98]
    DIRECTION OUTPUT ;
    USE SIGNAL ;
    PORT
      LAYER metal10 ;
        RECT  361.295 289.27 362.095 290.07 ;
    END
  END rsp_data[98]
  PIN rsp_data[99]
    DIRECTION OUTPUT ;
    USE SIGNAL ;
    PORT
      LAYER metal10 ;
        RECT  364.495 289.27 365.295 290.07 ;
    END
  END rsp_data[99]
  PIN rsp_data[9]
    DIRECTION OUTPUT ;
    USE SIGNAL ;
    PORT
      LAYER metal10 ;
        RECT  383.695 263.67 384.495 264.47 ;
    END
  END rsp_data[9]
  PIN rsp_error
    DIRECTION OUTPUT ;
    USE SIGNAL ;
    PORT
      LAYER metal10 ;
        RECT  1.295 68.47 2.095 69.27 ;
    END
  END rsp_error
  PIN rsp_ready
    DIRECTION INPUT ;
    USE SIGNAL ;
    PORT
      LAYER metal10 ;
        RECT  1.295 71.67 2.095 72.47 ;
    END
  END rsp_ready
  PIN rsp_saturated
    DIRECTION OUTPUT ;
    USE SIGNAL ;
    PORT
      LAYER metal10 ;
        RECT  1.295 74.87 2.095 75.67 ;
    END
  END rsp_saturated
  PIN rsp_valid
    DIRECTION OUTPUT ;
    USE SIGNAL ;
    PORT
      LAYER metal10 ;
        RECT  1.295 78.07 2.095 78.87 ;
    END
  END rsp_valid
  PIN VSS
    DIRECTION INOUT ;
    USE GROUND ;
    PORT
      LAYER metal7 ;
        RECT  20.14 532.3 539.98 533.7 ;
        RECT  20.14 502.3 539.98 503.7 ;
        RECT  20.14 472.3 539.98 473.7 ;
        RECT  20.14 442.3 539.98 443.7 ;
        RECT  20.14 412.3 539.98 413.7 ;
        RECT  20.14 382.3 539.98 383.7 ;
        RECT  20.14 352.3 539.98 353.7 ;
        RECT  20.14 322.3 539.98 323.7 ;
        RECT  20.14 292.3 539.98 293.7 ;
        RECT  20.14 262.3 539.98 263.7 ;
        RECT  20.14 232.3 539.98 233.7 ;
        RECT  20.14 202.3 539.98 203.7 ;
        RECT  20.14 172.3 539.98 173.7 ;
        RECT  20.14 142.3 539.98 143.7 ;
        RECT  20.14 112.3 539.98 113.7 ;
        RECT  20.14 82.3 539.98 83.7 ;
        RECT  20.14 52.3 539.98 53.7 ;
        RECT  20.14 22.3 539.98 23.7 ;
    END
  END VSS
  PIN VDD
    DIRECTION INOUT ;
    USE POWER ;
    PORT
      LAYER metal7 ;
        RECT  20.14 517.3 539.98 518.7 ;
        RECT  20.14 487.3 539.98 488.7 ;
        RECT  20.14 457.3 539.98 458.7 ;
        RECT  20.14 427.3 539.98 428.7 ;
        RECT  20.14 397.3 539.98 398.7 ;
        RECT  20.14 367.3 539.98 368.7 ;
        RECT  20.14 337.3 539.98 338.7 ;
        RECT  20.14 307.3 539.98 308.7 ;
        RECT  20.14 277.3 539.98 278.7 ;
        RECT  20.14 247.3 539.98 248.7 ;
        RECT  20.14 217.3 539.98 218.7 ;
        RECT  20.14 187.3 539.98 188.7 ;
        RECT  20.14 157.3 539.98 158.7 ;
        RECT  20.14 127.3 539.98 128.7 ;
        RECT  20.14 97.3 539.98 98.7 ;
        RECT  20.14 67.3 539.98 68.7 ;
        RECT  20.14 37.3 539.98 38.7 ;
    END
  END VDD
  OBS
    LAYER metal1 ;
     RECT  0.495 18.87 539.98 539.085 ;
    LAYER metal2 ;
     RECT  0.495 18.87 539.98 539.085 ;
    LAYER metal3 ;
     RECT  0.495 18.87 539.98 539.085 ;
    LAYER metal4 ;
     RECT  0.495 18.87 539.98 539.085 ;
    LAYER metal5 ;
     RECT  0.495 18.87 539.98 539.085 ;
    LAYER metal6 ;
     RECT  0.495 18.87 539.98 539.085 ;
    LAYER metal7 ;
     RECT  0.495 18.87 539.98 539.085 ;
    LAYER metal8 ;
     RECT  0.495 18.87 539.98 539.085 ;
    LAYER metal9 ;
     RECT  0.495 18.87 539.98 539.085 ;
    LAYER metal10 ;
     RECT  0.495 18.87 539.98 539.085 ;
  END
END block_v1_m
END LIBRARY
